VERSION 5.7 ;
  NOWIREEXTENSIONATPIN ON ;
  DIVIDERCHAR "/" ;
  BUSBITCHARS "[]" ;
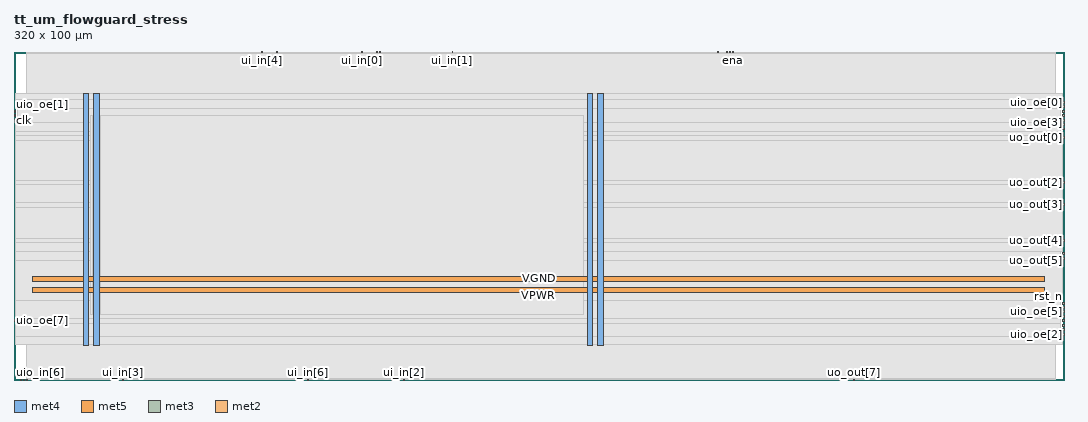
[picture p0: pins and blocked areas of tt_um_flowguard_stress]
MACRO tt_um_flowguard_stress
  CLASS BLOCK ;
  FOREIGN tt_um_flowguard_stress ;
  ORIGIN 0.000 0.000 ;
  SIZE 320.000 BY 100.000 ;
  PIN VGND
    DIRECTION INOUT ;
    USE GROUND ;
    PORT
      LAYER met4 ;
        RECT 24.340 10.640 25.940 87.280 ;
    END
    PORT
      LAYER met4 ;
        RECT 177.940 10.640 179.540 87.280 ;
    END
    PORT
      LAYER met5 ;
        RECT 5.520 30.030 314.180 31.630 ;
    END
  END VGND
  PIN VPWR
    DIRECTION INOUT ;
    USE POWER ;
    PORT
      LAYER met4 ;
        RECT 21.040 10.640 22.640 87.280 ;
    END
    PORT
      LAYER met4 ;
        RECT 174.640 10.640 176.240 87.280 ;
    END
    PORT
      LAYER met5 ;
        RECT 5.520 26.730 314.180 28.330 ;
    END
  END VPWR
  PIN clk
    DIRECTION INPUT ;
    USE SIGNAL ;
    ANTENNAGATEAREA 0.852000 ;
    PORT
      LAYER met3 ;
        RECT 0.000 78.920 0.600 79.520 ;
    END
  END clk
  PIN ena
    DIRECTION INPUT ;
    USE SIGNAL ;
    ANTENNAGATEAREA 0.213000 ;
    PORT
      LAYER met2 ;
        RECT 219.050 99.720 219.330 100.000 ;
    END
  END ena
  PIN rst_n
    DIRECTION INPUT ;
    USE SIGNAL ;
    ANTENNAGATEAREA 0.213000 ;
    PORT
      LAYER met3 ;
        RECT 319.400 23.160 320.000 23.760 ;
    END
  END rst_n
  PIN ui_in[0]
    DIRECTION INPUT ;
    USE SIGNAL ;
    ANTENNAGATEAREA 0.213000 ;
    PORT
      LAYER met2 ;
        RECT 105.890 99.720 106.170 100.000 ;
    END
  END ui_in[0]
  PIN ui_in[1]
    DIRECTION INPUT ;
    USE SIGNAL ;
    ANTENNAGATEAREA 0.213000 ;
    PORT
      LAYER met2 ;
        RECT 133.490 99.720 133.770 100.000 ;
    END
  END ui_in[1]
  PIN ui_in[2]
    DIRECTION INPUT ;
    USE SIGNAL ;
    ANTENNAGATEAREA 0.213000 ;
    PORT
      LAYER met2 ;
        RECT 118.770 0.000 119.050 0.280 ;
    END
  END ui_in[2]
  PIN ui_in[3]
    DIRECTION INPUT ;
    USE SIGNAL ;
    ANTENNAGATEAREA 0.213000 ;
    PORT
      LAYER met2 ;
        RECT 33.210 0.000 33.490 0.280 ;
    END
  END ui_in[3]
  PIN ui_in[4]
    DIRECTION INPUT ;
    USE SIGNAL ;
    ANTENNAGATEAREA 0.213000 ;
    PORT
      LAYER met2 ;
        RECT 75.530 99.720 75.810 100.000 ;
    END
  END ui_in[4]
  PIN ui_in[5]
    DIRECTION INPUT ;
    USE SIGNAL ;
    ANTENNAGATEAREA 0.213000 ;
    PORT
      LAYER met2 ;
        RECT 80.130 99.720 80.410 100.000 ;
    END
  END ui_in[5]
  PIN ui_in[6]
    DIRECTION INPUT ;
    USE SIGNAL ;
    ANTENNAGATEAREA 0.213000 ;
    PORT
      LAYER met2 ;
        RECT 89.330 0.000 89.610 0.280 ;
    END
  END ui_in[6]
  PIN ui_in[7]
    DIRECTION INPUT ;
    USE SIGNAL ;
    ANTENNAGATEAREA 0.213000 ;
    PORT
      LAYER met2 ;
        RECT 115.090 0.000 115.370 0.280 ;
    END
  END ui_in[7]
  PIN uio_in[0]
    DIRECTION INPUT ;
    USE SIGNAL ;
    ANTENNAGATEAREA 0.213000 ;
    PORT
      LAYER met2 ;
        RECT 218.130 99.720 218.410 100.000 ;
    END
  END uio_in[0]
  PIN uio_in[1]
    DIRECTION INPUT ;
    USE SIGNAL ;
    ANTENNAGATEAREA 0.213000 ;
    PORT
      LAYER met2 ;
        RECT 217.210 99.720 217.490 100.000 ;
    END
  END uio_in[1]
  PIN uio_in[2]
    DIRECTION INPUT ;
    USE SIGNAL ;
    ANTENNAGATEAREA 0.213000 ;
    PORT
      LAYER met2 ;
        RECT 111.410 99.720 111.690 100.000 ;
    END
  END uio_in[2]
  PIN uio_in[3]
    DIRECTION INPUT ;
    USE SIGNAL ;
    ANTENNAGATEAREA 0.213000 ;
    PORT
      LAYER met2 ;
        RECT 110.490 99.720 110.770 100.000 ;
    END
  END uio_in[3]
  PIN uio_in[4]
    DIRECTION INPUT ;
    USE SIGNAL ;
    ANTENNAGATEAREA 0.213000 ;
    PORT
      LAYER met2 ;
        RECT 214.450 99.720 214.730 100.000 ;
    END
  END uio_in[4]
  PIN uio_in[5]
    DIRECTION INPUT ;
    USE SIGNAL ;
    PORT
      LAYER met2 ;
        RECT 1.930 0.000 2.210 0.280 ;
    END
  END uio_in[5]
  PIN uio_in[6]
    DIRECTION INPUT ;
    USE SIGNAL ;
    PORT
      LAYER met2 ;
        RECT 2.850 0.000 3.130 0.280 ;
    END
  END uio_in[6]
  PIN uio_in[7]
    DIRECTION INPUT ;
    USE SIGNAL ;
    PORT
      LAYER met2 ;
        RECT 3.770 0.000 4.050 0.280 ;
    END
  END uio_in[7]
  PIN uio_oe[0]
    DIRECTION OUTPUT ;
    USE SIGNAL ;
    PORT
      LAYER met3 ;
        RECT 319.400 84.360 320.000 84.960 ;
    END
  END uio_oe[0]
  PIN uio_oe[1]
    DIRECTION OUTPUT ;
    USE SIGNAL ;
    PORT
      LAYER met3 ;
        RECT 0.000 81.640 0.600 82.240 ;
    END
  END uio_oe[1]
  PIN uio_oe[2]
    DIRECTION OUTPUT ;
    USE SIGNAL ;
    PORT
      LAYER met3 ;
        RECT 319.400 13.640 320.000 14.240 ;
    END
  END uio_oe[2]
  PIN uio_oe[3]
    DIRECTION OUTPUT ;
    USE SIGNAL ;
    PORT
      LAYER met3 ;
        RECT 319.400 80.280 320.000 80.880 ;
    END
  END uio_oe[3]
  PIN uio_oe[4]
    DIRECTION OUTPUT ;
    USE SIGNAL ;
    PORT
      LAYER met3 ;
        RECT 319.400 83.000 320.000 83.600 ;
    END
  END uio_oe[4]
  PIN uio_oe[5]
    DIRECTION OUTPUT ;
    USE SIGNAL ;
    PORT
      LAYER met3 ;
        RECT 319.400 20.440 320.000 21.040 ;
    END
  END uio_oe[5]
  PIN uio_oe[6]
    DIRECTION OUTPUT ;
    USE SIGNAL ;
    PORT
      LAYER met3 ;
        RECT 319.400 16.360 320.000 16.960 ;
    END
  END uio_oe[6]
  PIN uio_oe[7]
    DIRECTION OUTPUT ;
    USE SIGNAL ;
    PORT
      LAYER met3 ;
        RECT 0.000 17.720 0.600 18.320 ;
    END
  END uio_oe[7]
  PIN uio_out[0]
    DIRECTION OUTPUT ;
    USE SIGNAL ;
    PORT
      LAYER met3 ;
        RECT 319.400 81.640 320.000 82.240 ;
    END
  END uio_out[0]
  PIN uio_out[1]
    DIRECTION OUTPUT ;
    USE SIGNAL ;
    PORT
      LAYER met3 ;
        RECT 319.400 15.000 320.000 15.600 ;
    END
  END uio_out[1]
  PIN uio_out[2]
    DIRECTION OUTPUT ;
    USE SIGNAL ;
    PORT
      LAYER met3 ;
        RECT 319.400 78.920 320.000 79.520 ;
    END
  END uio_out[2]
  PIN uio_out[3]
    DIRECTION OUTPUT ;
    USE SIGNAL ;
    PORT
      LAYER met3 ;
        RECT 319.400 77.560 320.000 78.160 ;
    END
  END uio_out[3]
  PIN uio_out[4]
    DIRECTION OUTPUT ;
    USE SIGNAL ;
    PORT
      LAYER met3 ;
        RECT 319.400 21.800 320.000 22.400 ;
    END
  END uio_out[4]
  PIN uio_out[5]
    DIRECTION OUTPUT ;
    USE SIGNAL ;
    PORT
      LAYER met3 ;
        RECT 319.400 19.080 320.000 19.680 ;
    END
  END uio_out[5]
  PIN uio_out[6]
    DIRECTION OUTPUT ;
    USE SIGNAL ;
    PORT
      LAYER met3 ;
        RECT 0.000 80.280 0.600 80.880 ;
    END
  END uio_out[6]
  PIN uio_out[7]
    DIRECTION OUTPUT ;
    USE SIGNAL ;
    PORT
      LAYER met3 ;
        RECT 319.400 17.720 320.000 18.320 ;
    END
  END uio_out[7]
  PIN uo_out[0]
    DIRECTION OUTPUT ;
    USE SIGNAL ;
    ANTENNADIFFAREA 0.702900 ;
    PORT
      LAYER met3 ;
        RECT 319.400 73.480 320.000 74.080 ;
    END
  END uo_out[0]
  PIN uo_out[1]
    DIRECTION OUTPUT ;
    USE SIGNAL ;
    ANTENNADIFFAREA 0.702900 ;
    PORT
      LAYER met3 ;
        RECT 319.400 76.200 320.000 76.800 ;
    END
  END uo_out[1]
  PIN uo_out[2]
    DIRECTION OUTPUT ;
    USE SIGNAL ;
    ANTENNADIFFAREA 0.702900 ;
    PORT
      LAYER met3 ;
        RECT 319.400 59.880 320.000 60.480 ;
    END
  END uo_out[2]
  PIN uo_out[3]
    DIRECTION OUTPUT ;
    USE SIGNAL ;
    ANTENNADIFFAREA 0.702900 ;
    PORT
      LAYER met3 ;
        RECT 319.400 53.080 320.000 53.680 ;
    END
  END uo_out[3]
  PIN uo_out[4]
    DIRECTION OUTPUT ;
    USE SIGNAL ;
    ANTENNADIFFAREA 0.702900 ;
    PORT
      LAYER met3 ;
        RECT 319.400 42.200 320.000 42.800 ;
    END
  END uo_out[4]
  PIN uo_out[5]
    DIRECTION OUTPUT ;
    USE SIGNAL ;
    ANTENNADIFFAREA 0.702900 ;
    PORT
      LAYER met3 ;
        RECT 319.400 38.120 320.000 38.720 ;
    END
  END uo_out[5]
  PIN uo_out[6]
    DIRECTION OUTPUT ;
    USE SIGNAL ;
    ANTENNADIFFAREA 0.702900 ;
    PORT
      LAYER met3 ;
        RECT 319.400 36.760 320.000 37.360 ;
    END
  END uo_out[6]
  PIN uo_out[7]
    DIRECTION OUTPUT ;
    USE SIGNAL ;
    ANTENNADIFFAREA 0.702900 ;
    PORT
      LAYER met2 ;
        RECT 255.850 0.000 256.130 0.280 ;
    END
  END uo_out[7]
  OBS
      LAYER nwell ;
        RECT 5.330 10.795 314.370 87.125 ;
      LAYER li1 ;
        RECT 5.520 10.795 314.180 87.125 ;
      LAYER met1 ;
        RECT 3.750 10.640 317.330 87.280 ;
      LAYER met2 ;
        RECT 3.770 99.440 75.250 99.720 ;
        RECT 76.090 99.440 79.850 99.720 ;
        RECT 80.690 99.440 105.610 99.720 ;
        RECT 106.450 99.440 110.210 99.720 ;
        RECT 111.050 99.440 111.130 99.720 ;
        RECT 111.970 99.440 133.210 99.720 ;
        RECT 134.050 99.440 214.170 99.720 ;
        RECT 215.010 99.440 216.930 99.720 ;
        RECT 217.770 99.440 217.850 99.720 ;
        RECT 218.690 99.440 218.770 99.720 ;
        RECT 219.610 99.440 317.310 99.720 ;
        RECT 3.770 0.560 317.310 99.440 ;
        RECT 4.330 0.280 32.930 0.560 ;
        RECT 33.770 0.280 89.050 0.560 ;
        RECT 89.890 0.280 114.810 0.560 ;
        RECT 115.650 0.280 118.490 0.560 ;
        RECT 119.330 0.280 255.570 0.560 ;
        RECT 256.410 0.280 317.310 0.560 ;
      LAYER met3 ;
        RECT 0.600 85.360 319.400 87.205 ;
        RECT 0.600 82.640 319.000 85.360 ;
        RECT 1.000 78.520 319.000 82.640 ;
        RECT 0.600 75.800 319.000 78.520 ;
        RECT 0.600 74.480 319.400 75.800 ;
        RECT 0.600 73.080 319.000 74.480 ;
        RECT 0.600 60.880 319.400 73.080 ;
        RECT 0.600 59.480 319.000 60.880 ;
        RECT 0.600 54.080 319.400 59.480 ;
        RECT 0.600 52.680 319.000 54.080 ;
        RECT 0.600 43.200 319.400 52.680 ;
        RECT 0.600 41.800 319.000 43.200 ;
        RECT 0.600 39.120 319.400 41.800 ;
        RECT 0.600 36.360 319.000 39.120 ;
        RECT 0.600 24.160 319.400 36.360 ;
        RECT 0.600 18.720 319.000 24.160 ;
        RECT 1.000 17.320 319.000 18.720 ;
        RECT 0.600 13.240 319.000 17.320 ;
        RECT 0.600 10.715 319.400 13.240 ;
      LAYER met4 ;
        RECT 23.295 19.895 23.940 80.745 ;
        RECT 26.340 19.895 173.585 80.745 ;
  END
END tt_um_flowguard_stress
END LIBRARY

